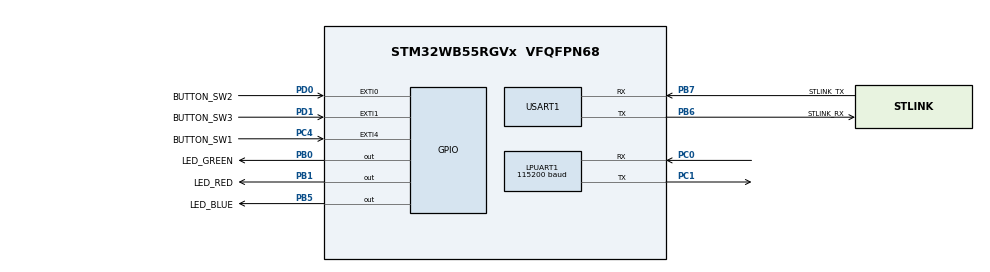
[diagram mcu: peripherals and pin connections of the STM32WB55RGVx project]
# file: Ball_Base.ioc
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Dma.LPUART1_TX.1.Direction=DMA_MEMORY_TO_PERIPH
Dma.LPUART1_TX.1.EventEnable=DISABLE
Dma.LPUART1_TX.1.Instance=DMA1_Channel4
Dma.LPUART1_TX.1.MemDataAlignment=DMA_MDATAALIGN_BYTE
Dma.LPUART1_TX.1.MemInc=DMA_MINC_ENABLE
Dma.LPUART1_TX.1.Mode=DMA_NORMAL
Dma.LPUART1_TX.1.PeriphDataAlignment=DMA_PDATAALIGN_BYTE
Dma.LPUART1_TX.1.PeriphInc=DMA_PINC_DISABLE
Dma.LPUART1_TX.1.Polarity=HAL_DMAMUX_REQ_GEN_RISING
Dma.LPUART1_TX.1.Priority=DMA_PRIORITY_LOW
Dma.LPUART1_TX.1.RequestNumber=1
Dma.LPUART1_TX.1.SignalID=NONE
Dma.LPUART1_TX.1.SyncEnable=DISABLE
Dma.LPUART1_TX.1.SyncPolarity=HAL_DMAMUX_SYNC_NO_EVENT
Dma.LPUART1_TX.1.SyncRequestNumber=1
Dma.LPUART1_TX.1.SyncSignalID=NONE
Dma.Request0=USART1_TX
Dma.Request1=LPUART1_TX
Dma.USART1_TX.0.Direction=DMA_MEMORY_TO_PERIPH
Dma.USART1_TX.0.EventEnable=DISABLE
Dma.USART1_TX.0.Instance=DMA2_Channel4
Dma.USART1_TX.0.MemDataAlignment=DMA_MDATAALIGN_BYTE
Dma.USART1_TX.0.MemInc=DMA_MINC_ENABLE
Dma.USART1_TX.0.Mode=DMA_NORMAL
Dma.USART1_TX.0.PeriphDataAlignment=DMA_PDATAALIGN_BYTE
Dma.USART1_TX.0.PeriphInc=DMA_PINC_DISABLE
Dma.USART1_TX.0.Polarity=HAL_DMAMUX_REQ_GEN_RISING
Dma.USART1_TX.0.Priority=DMA_PRIORITY_LOW
Dma.USART1_TX.0.RequestNumber=1
Dma.USART1_TX.0.SignalID=NONE
Dma.USART1_TX.0.SyncEnable=DISABLE
Dma.USART1_TX.0.SyncPolarity=HAL_DMAMUX_SYNC_NO_EVENT
Dma.USART1_TX.0.SyncRequestNumber=1
Dma.USART1_TX.0.SyncSignalID=NONE
LPUART1.BaudRate=115200
Mcu.Family=STM32WB
Mcu.Name=STM32WB55RGVx
Mcu.Package=VFQFPN68
NVIC.DMA1_Channel4_IRQn=true\:15\:0\:true\:false\:true\:false\:true\:true
NVIC.DMA2_Channel4_IRQn=true\:15\:0\:true\:false\:true\:false\:true\:true
NVIC.EXTI0_IRQn=true\:3\:0\:true\:false\:true\:true\:true\:true
NVIC.EXTI1_IRQn=true\:3\:0\:true\:false\:true\:true\:true\:true
NVIC.EXTI4_IRQn=true\:3\:0\:true\:false\:true\:true\:true\:true
NVIC.HSEM_IRQn=true\:0\:0\:false\:false\:true\:false\:true\:true
NVIC.IPCC_C1_RX_IRQn=true\:0\:0\:false\:false\:true\:true\:true\:true
NVIC.IPCC_C1_TX_IRQn=true\:0\:0\:false\:false\:true\:true\:true\:true
NVIC.LPUART1_IRQn=true\:0\:0\:false\:false\:true\:true\:true\:true
NVIC.PriorityGroup=NVIC_PRIORITYGROUP_4
NVIC.USART1_IRQn=true\:0\:0\:false\:false\:true\:true\:true\:true
OSC_IN.Mode=HSE-External-Oscillator
OSC_IN.Signal=RCC_OSC_IN
OSC_OUT.Mode=HSE-External-Oscillator
OSC_OUT.Signal=RCC_OSC_OUT
PA13.GPIO_Label=JTMS
PA13.Mode=Trace_Asynchronous_SW
PA13.Signal=SYS_JTMS-SWDIO
PA14.GPIO_Label=JTCK
PA14.Mode=Trace_Asynchronous_SW
PA14.Signal=SYS_JTCK-SWCLK
PB0.GPIO_Label=LED_GREEN
PB0.Signal=GPIO_Output
PB1.GPIO_Label=LED_RED
PB1.Signal=GPIO_Output
PB3.GPIO_Label=JTDO
PB3.Mode=Trace_Asynchronous_SW
PB3.Signal=SYS_JTDO-SWO
PB5.GPIO_Label=LED_BLUE
PB5.Signal=GPIO_Output
PB6.GPIO_Label=STLINK_RX
PB6.GPIO_PuPd=GPIO_PULLUP
PB6.Mode=Asynchronous
PB6.Signal=USART1_TX
PB7.GPIO_Label=STLINK_TX
PB7.GPIO_PuPd=GPIO_PULLUP
PB7.Mode=Asynchronous
PB7.Signal=USART1_RX
PC0.Mode=Asynchronous
PC0.Signal=LPUART1_RX
PC1.Mode=Asynchronous
PC1.Signal=LPUART1_TX
PC13.Mode=SYS_WakeUp1
PC13.Signal=SYS_WKUP2
PC14-OSC32_IN.Mode=LSE-External-Oscillator
PC14-OSC32_IN.Signal=RCC_OSC32_IN
PC15-OSC32_OUT.Mode=LSE-External-Oscillator
PC15-OSC32_OUT.Signal=RCC_OSC32_OUT
PC4.GPIO_Label=BUTTON_SW1
PC4.GPIO_ModeDefaultEXTI=GPIO_MODE_IT_FALLING
PC4.GPIO_PuPd=GPIO_PULLUP
PC4.Signal=GPXTI4
PD0.GPIO_Label=BUTTON_SW2
PD0.GPIO_ModeDefaultEXTI=GPIO_MODE_IT_FALLING
PD0.GPIO_PuPd=GPIO_PULLUP
PD0.Signal=GPXTI0
PD1.GPIO_Label=BUTTON_SW3
PD1.GPIO_ModeDefaultEXTI=GPIO_MODE_IT_FALLING
PD1.GPIO_PuPd=GPIO_PULLUP
PD1.Signal=GPXTI1
ProjectManager.HeapSize=0x200
ProjectManager.StackSize=0x400
ProjectManager.TargetToolchain=STM32CubeIDE
RCC.ADCFreq_Value=96000000
RCC.AHB2CLKDivider=RCC_SYSCLK_DIV2
RCC.AHBFreq_Value=64000000
RCC.APB1Freq_Value=64000000
RCC.APB1TimFreq_Value=64000000
RCC.APB2Freq_Value=64000000
RCC.APB2TimFreq_Value=64000000
RCC.APB3Freq_Value=16000000
RCC.CortexFreq_Value=64000000
RCC.HCLKFreq_Value=64000000
RCC.HSE_VALUE=32000000
RCC.HSI48_VALUE=48000000
RCC.HSI_VALUE=16000000
RCC.PLLM=RCC_PLLM_DIV4
RCC.PLLN=32
RCC.PLLR=RCC_PLLR_DIV4
RCC.PLLSAI1N=24
RCC.PLLSourceVirtual=RCC_PLLSOURCE_HSE
RCC.RFWKPClockSelection=RCC_RFWKPCLKSOURCE_LSE
RCC.RTCClockSelection=RCC_RTCCLKSOURCE_LSE
RCC.SMPSCLockSelectionVirtual=RCC_SMPSCLKSOURCE_HSI
RCC.SMPSCLockSelectionVirtualVirtual=RCC_SMPSCLKSOURCE_HSI
RCC.SYSCLKFreq_VALUE=64000000
RCC.SYSCLKSource=RCC_SYSCLKSOURCE_PLLCLK
RCC.USBFreq_Value=96000000
RCC.VCOOutputFreq_Value=256000000
RF1.Mode=RF1_Activate
RF1.Signal=RF_RF1
STM32_WPAN.BLE_APPLICATION_TYPE=BLE_CLIENT_PROFILE
STM32_WPAN.BLE_DBG_APP_EN=1
STM32_WPAN.CFG_ADV_BD_ADDRESS=0x7257acd87a6c
STM32_WPAN.CFG_CONSOLE_MENU=No UART selected
STM32_WPAN.CFG_DEBUG_APP_TRACE=1
STM32_WPAN.CFG_DEBUG_BLE_TRACE=1
STM32_WPAN.CFG_DEBUG_TRACE_LIGHT=1
STM32_WPAN.CFG_DEBUG_TRACE_UART=hw_uart1
STM32_WPAN.CFG_HW_LPUART1_ENABLED=0
STM32_WPAN.CFG_HW_USART1_ENABLED=1
STM32_WPAN.CFG_IO_CAPABILITY=CFG_IO_CAPABILITY_DISPLAY_YES_NO
STM32_WPAN.CFG_LPM_SUPPORTED=1
STM32_WPAN.DBG_TRACE_USE_CIRCULAR_QUEUE=0
STM32_WPAN.LOCAL_NAME=MJOY_CL
STM32_WPAN.LOCAL_NAME_FORMATTED=,'M','J','O','Y','_','C','L'
USART1.VirtualMode-Asynchronous=VM_ASYNC
USART1.WordLength=WORDLENGTH_8B
VP_HSEM_VS_HSEM.Mode=HSEM_Activate
VP_IPCC_VS_IPCC.Mode=IPCC_Activate
VP_RTC_VS_RTC_Activate.Mode=RTC_Enabled
VP_RTC_VS_RTC_WakeUp_intern.Mode=WakeUp
VP_SEQUENCER_VS_SEQUENCER.Mode=SEQUENCER_Enabled
VP_STM32_WPAN_VS_BLE_HOST.Mode=STM32_WPAN_Enabled
VP_TINY_LPM_VS_TINY_LPM.Mode=TINY_LPM_Enabled
board=NUCLEO-WB55RG

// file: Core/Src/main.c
/* USER CODE BEGIN Header */
/**
  ******************************************************************************
  * @file           : main.c
  * @brief          : Main program body
  ******************************************************************************
  * @attention
  *
  * <h2><center>&copy; Copyright (c) 2021 STMicroelectronics.
  * All rights reserved.</center></h2>
  *
  * This software component is licensed by ST under BSD 3-Clause license,
  * the "License"; You may not use this file except in compliance with the
  * License. You may obtain a copy of the License at:
  *                        opensource.org/licenses/BSD-3-Clause
  *
  ******************************************************************************
  */
/* USER CODE END Header */
#include "main.h"

/* USER CODE BEGIN Includes */
#include "initialisation.h"
/* USER CODE END Includes */

IPCC_HandleTypeDef hipcc;

UART_HandleTypeDef hlpuart1;
UART_HandleTypeDef huart1;
DMA_HandleTypeDef hdma_lpuart1_tx;
DMA_HandleTypeDef hdma_usart1_tx;

RTC_HandleTypeDef hrtc;

void SystemClock_Config(void);
static void MX_GPIO_Init(void);
static void MX_IPCC_Init(void);
static void MX_RF_Init(void);
static void MX_RTC_Init(void);
static void MX_DMA_Init(void);
static void MX_LPUART1_UART_Init(void);

int main(void)
{

  /* MCU Configuration--------------------------------------------------------*/

  /* Reset of all peripherals, Initializes the Flash interface and the Systick. */
  HAL_Init();
  /* Config code for STM32_WPAN (HSE Tuning must be done before system clock configuration) */
  MX_APPE_Config();

  /* Configure the system clock */
  SystemClock_Config();

  /* IPCC initialisation */
   MX_IPCC_Init();

  /* Initialize all configured peripherals */
  MX_GPIO_Init();
  MX_RF_Init();
  MX_RTC_Init();
  MX_DMA_Init();
  MX_LPUART1_UART_Init();

  /* Init code for STM32_WPAN */
  MX_APPE_Init();
  /* Infinite loop */
  /* USER CODE BEGIN WHILE */
  MX_GPIO_Init();
  MX_USART1_UART_Init();
  InitTimer();
  while (1)
  {
    /* USER CODE END WHILE */
    MX_APPE_Process();

  }
}

void SystemClock_Config(void)
{
  RCC_OscInitTypeDef RCC_OscInitStruct = {0};
  RCC_ClkInitTypeDef RCC_ClkInitStruct = {0};
  RCC_PeriphCLKInitTypeDef PeriphClkInitStruct = {0};

  /** Configure LSE Drive Capability
  */
  HAL_PWR_EnableBkUpAccess();
  __HAL_RCC_LSEDRIVE_CONFIG(RCC_LSEDRIVE_LOW);
  /** Configure the main internal regulator output voltage
  */
  __HAL_PWR_VOLTAGESCALING_CONFIG(PWR_REGULATOR_VOLTAGE_SCALE1);
  /** Initializes the RCC Oscillators according to the specified parameters
  * in the RCC_OscInitTypeDef structure.
  */
  RCC_OscInitStruct.OscillatorType = RCC_OSCILLATORTYPE_HSI|RCC_OSCILLATORTYPE_HSE
                              |RCC_OSCILLATORTYPE_LSE;
  RCC_OscInitStruct.HSEState = RCC_HSE_ON;
  RCC_OscInitStruct.LSEState = RCC_LSE_ON;
  RCC_OscInitStruct.HSIState = RCC_HSI_ON;
  RCC_OscInitStruct.HSICalibrationValue = RCC_HSICALIBRATION_DEFAULT;
  RCC_OscInitStruct.PLL.PLLState = RCC_PLL_NONE;
  if (HAL_RCC_OscConfig(&RCC_OscInitStruct) != HAL_OK)
  {
    Error_Handler();
  }
  /** Configure the SYSCLKSource, HCLK, PCLK1 and PCLK2 clocks dividers
  */
  RCC_ClkInitStruct.ClockType = RCC_CLOCKTYPE_HCLK4|RCC_CLOCKTYPE_HCLK2
                              |RCC_CLOCKTYPE_HCLK|RCC_CLOCKTYPE_SYSCLK
                              |RCC_CLOCKTYPE_PCLK1|RCC_CLOCKTYPE_PCLK2;
  RCC_ClkInitStruct.SYSCLKSource = RCC_SYSCLKSOURCE_HSE;
  RCC_ClkInitStruct.AHBCLKDivider = RCC_SYSCLK_DIV1;
  RCC_ClkInitStruct.APB1CLKDivider = RCC_HCLK_DIV1;
  RCC_ClkInitStruct.APB2CLKDivider = RCC_HCLK_DIV1;
  RCC_ClkInitStruct.AHBCLK2Divider = RCC_SYSCLK_DIV1;
  RCC_ClkInitStruct.AHBCLK4Divider = RCC_SYSCLK_DIV1;

  if (HAL_RCC_ClockConfig(&RCC_ClkInitStruct, FLASH_LATENCY_1) != HAL_OK)
  {
    Error_Handler();
  }
  /** Initializes the peripherals clocks
  */
  PeriphClkInitStruct.PeriphClockSelection = RCC_PERIPHCLK_SMPS|RCC_PERIPHCLK_RFWAKEUP
                              |RCC_PERIPHCLK_RTC|RCC_PERIPHCLK_USART1
                              |RCC_PERIPHCLK_LPUART1;
  PeriphClkInitStruct.Usart1ClockSelection = RCC_USART1CLKSOURCE_PCLK2;
  PeriphClkInitStruct.Lpuart1ClockSelection = RCC_LPUART1CLKSOURCE_PCLK1;
  PeriphClkInitStruct.RTCClockSelection = RCC_RTCCLKSOURCE_LSE;
  PeriphClkInitStruct.RFWakeUpClockSelection = RCC_RFWKPCLKSOURCE_LSE;
  PeriphClkInitStruct.SmpsClockSelection = RCC_SMPSCLKSOURCE_HSI;
  PeriphClkInitStruct.SmpsDivSelection = RCC_SMPSCLKDIV_RANGE1;
  if (HAL_RCCEx_PeriphCLKConfig(&PeriphClkInitStruct) != HAL_OK)
  {
    Error_Handler();
  }
}

static void MX_IPCC_Init(void)
{

  hipcc.Instance = IPCC;
  if (HAL_IPCC_Init(&hipcc) != HAL_OK)
  {
    Error_Handler();
  }

}

static void MX_LPUART1_UART_Init(void)
{

  hlpuart1.Instance = LPUART1;
  hlpuart1.Init.BaudRate = 115200;
  hlpuart1.Init.WordLength = UART_WORDLENGTH_8B;
  hlpuart1.Init.StopBits = UART_STOPBITS_1;
  hlpuart1.Init.Parity = UART_PARITY_NONE;
  hlpuart1.Init.Mode = UART_MODE_TX_RX;
  hlpuart1.Init.HwFlowCtl = UART_HWCONTROL_NONE;
  hlpuart1.Init.OneBitSampling = UART_ONE_BIT_SAMPLE_DISABLE;
  hlpuart1.Init.ClockPrescaler = UART_PRESCALER_DIV1;
  hlpuart1.AdvancedInit.AdvFeatureInit = UART_ADVFEATURE_NO_INIT;
  hlpuart1.FifoMode = UART_FIFOMODE_DISABLE;
  if (HAL_UART_Init(&hlpuart1) != HAL_OK)
  {
    Error_Handler();
  }
  if (HAL_UARTEx_SetTxFifoThreshold(&hlpuart1, UART_TXFIFO_THRESHOLD_1_8) != HAL_OK)
  {
    Error_Handler();
  }
  if (HAL_UARTEx_SetRxFifoThreshold(&hlpuart1, UART_RXFIFO_THRESHOLD_1_8) != HAL_OK)
  {
    Error_Handler();
  }
  if (HAL_UARTEx_DisableFifoMode(&hlpuart1) != HAL_OK)
  {
    Error_Handler();
  }

}

void MX_USART1_UART_Init(void)
{

  huart1.Instance = USART1;
  huart1.Init.BaudRate = 115200;
  huart1.Init.WordLength = UART_WORDLENGTH_8B;
  huart1.Init.StopBits = UART_STOPBITS_1;
  huart1.Init.Parity = UART_PARITY_NONE;
  huart1.Init.Mode = UART_MODE_TX_RX;
  huart1.Init.HwFlowCtl = UART_HWCONTROL_NONE;
  huart1.Init.OverSampling = UART_OVERSAMPLING_8;
  huart1.Init.OneBitSampling = UART_ONE_BIT_SAMPLE_DISABLE;
  huart1.Init.ClockPrescaler = UART_PRESCALER_DIV1;
  huart1.AdvancedInit.AdvFeatureInit = UART_ADVFEATURE_NO_INIT;
  if (HAL_UART_Init(&huart1) != HAL_OK)
  {
    Error_Handler();
  }
  if (HAL_UARTEx_SetTxFifoThreshold(&huart1, UART_TXFIFO_THRESHOLD_1_8) != HAL_OK)
  {
    Error_Handler();
  }
  if (HAL_UARTEx_SetRxFifoThreshold(&huart1, UART_RXFIFO_THRESHOLD_1_8) != HAL_OK)
  {
    Error_Handler();
  }
  if (HAL_UARTEx_DisableFifoMode(&huart1) != HAL_OK)
  {
    Error_Handler();
  }

}

static void MX_RF_Init(void)
{

}

static void MX_RTC_Init(void)
{

  /** Initialize RTC Only
  */
  hrtc.Instance = RTC;
  hrtc.Init.HourFormat = RTC_HOURFORMAT_24;
  hrtc.Init.AsynchPrediv = CFG_RTC_ASYNCH_PRESCALER;
  hrtc.Init.SynchPrediv = CFG_RTC_SYNCH_PRESCALER;
  hrtc.Init.OutPut = RTC_OUTPUT_DISABLE;
  hrtc.Init.OutPutPolarity = RTC_OUTPUT_POLARITY_HIGH;
  hrtc.Init.OutPutType = RTC_OUTPUT_TYPE_OPENDRAIN;
  hrtc.Init.OutPutRemap = RTC_OUTPUT_REMAP_NONE;
  if (HAL_RTC_Init(&hrtc) != HAL_OK)
  {
    Error_Handler();
  }
  /** Enable the WakeUp
  */
  if (HAL_RTCEx_SetWakeUpTimer(&hrtc, 0, RTC_WAKEUPCLOCK_RTCCLK_DIV16) != HAL_OK)
  {
    Error_Handler();
  }

}

static void MX_DMA_Init(void)
{

  /* DMA controller clock enable */
  __HAL_RCC_DMAMUX1_CLK_ENABLE();
  __HAL_RCC_DMA2_CLK_ENABLE();
  __HAL_RCC_DMA1_CLK_ENABLE();

  /* DMA interrupt init */
  /* DMA1_Channel4_IRQn interrupt configuration */
  HAL_NVIC_SetPriority(DMA1_Channel4_IRQn, 15, 0);
  HAL_NVIC_EnableIRQ(DMA1_Channel4_IRQn);
  /* DMA2_Channel4_IRQn interrupt configuration */
  HAL_NVIC_SetPriority(DMA2_Channel4_IRQn, 15, 0);
  HAL_NVIC_EnableIRQ(DMA2_Channel4_IRQn);

}

static void MX_GPIO_Init(void)
{
  GPIO_InitTypeDef GPIO_InitStruct = {0};

  /* GPIO Ports Clock Enable */
  __HAL_RCC_GPIOC_CLK_ENABLE();
  __HAL_RCC_GPIOB_CLK_ENABLE();
  __HAL_RCC_GPIOA_CLK_ENABLE();
  __HAL_RCC_GPIOD_CLK_ENABLE();

  /*Configure GPIO pin Output Level */
  HAL_GPIO_WritePin(GPIOB, LED_GREEN_Pin|LED_RED_Pin|LED_BLUE_Pin, GPIO_PIN_RESET);

  /*Configure GPIO pin : BUTTON_SW1_Pin */
  GPIO_InitStruct.Pin = BUTTON_SW1_Pin;
  GPIO_InitStruct.Mode = GPIO_MODE_IT_FALLING;
  GPIO_InitStruct.Pull = GPIO_PULLUP;
  HAL_GPIO_Init(BUTTON_SW1_GPIO_Port, &GPIO_InitStruct);

  /*Configure GPIO pins : LED_GREEN_Pin LED_RED_Pin LED_BLUE_Pin */
  GPIO_InitStruct.Pin = LED_GREEN_Pin|LED_RED_Pin|LED_BLUE_Pin;
  GPIO_InitStruct.Mode = GPIO_MODE_OUTPUT_PP;
  GPIO_InitStruct.Pull = GPIO_NOPULL;
  GPIO_InitStruct.Speed = GPIO_SPEED_FREQ_LOW;
  HAL_GPIO_Init(GPIOB, &GPIO_InitStruct);

  /*Configure GPIO pins : BUTTON_SW2_Pin BUTTON_SW3_Pin */
  GPIO_InitStruct.Pin = BUTTON_SW2_Pin|BUTTON_SW3_Pin;
  GPIO_InitStruct.Mode = GPIO_MODE_IT_FALLING;
  GPIO_InitStruct.Pull = GPIO_PULLUP;
  HAL_GPIO_Init(GPIOD, &GPIO_InitStruct);

  /* EXTI interrupt init*/
  HAL_NVIC_SetPriority(EXTI0_IRQn, 3, 0);
  HAL_NVIC_EnableIRQ(EXTI0_IRQn);

  HAL_NVIC_SetPriority(EXTI1_IRQn, 3, 0);
  HAL_NVIC_EnableIRQ(EXTI1_IRQn);

  HAL_NVIC_SetPriority(EXTI4_IRQn, 3, 0);
  HAL_NVIC_EnableIRQ(EXTI4_IRQn);

}

void Error_Handler(void)
{
  __disable_irq();
  while (1)
  {
  }
}

/************************ (C) COPYRIGHT STMicroelectronics *****END OF FILE****/
